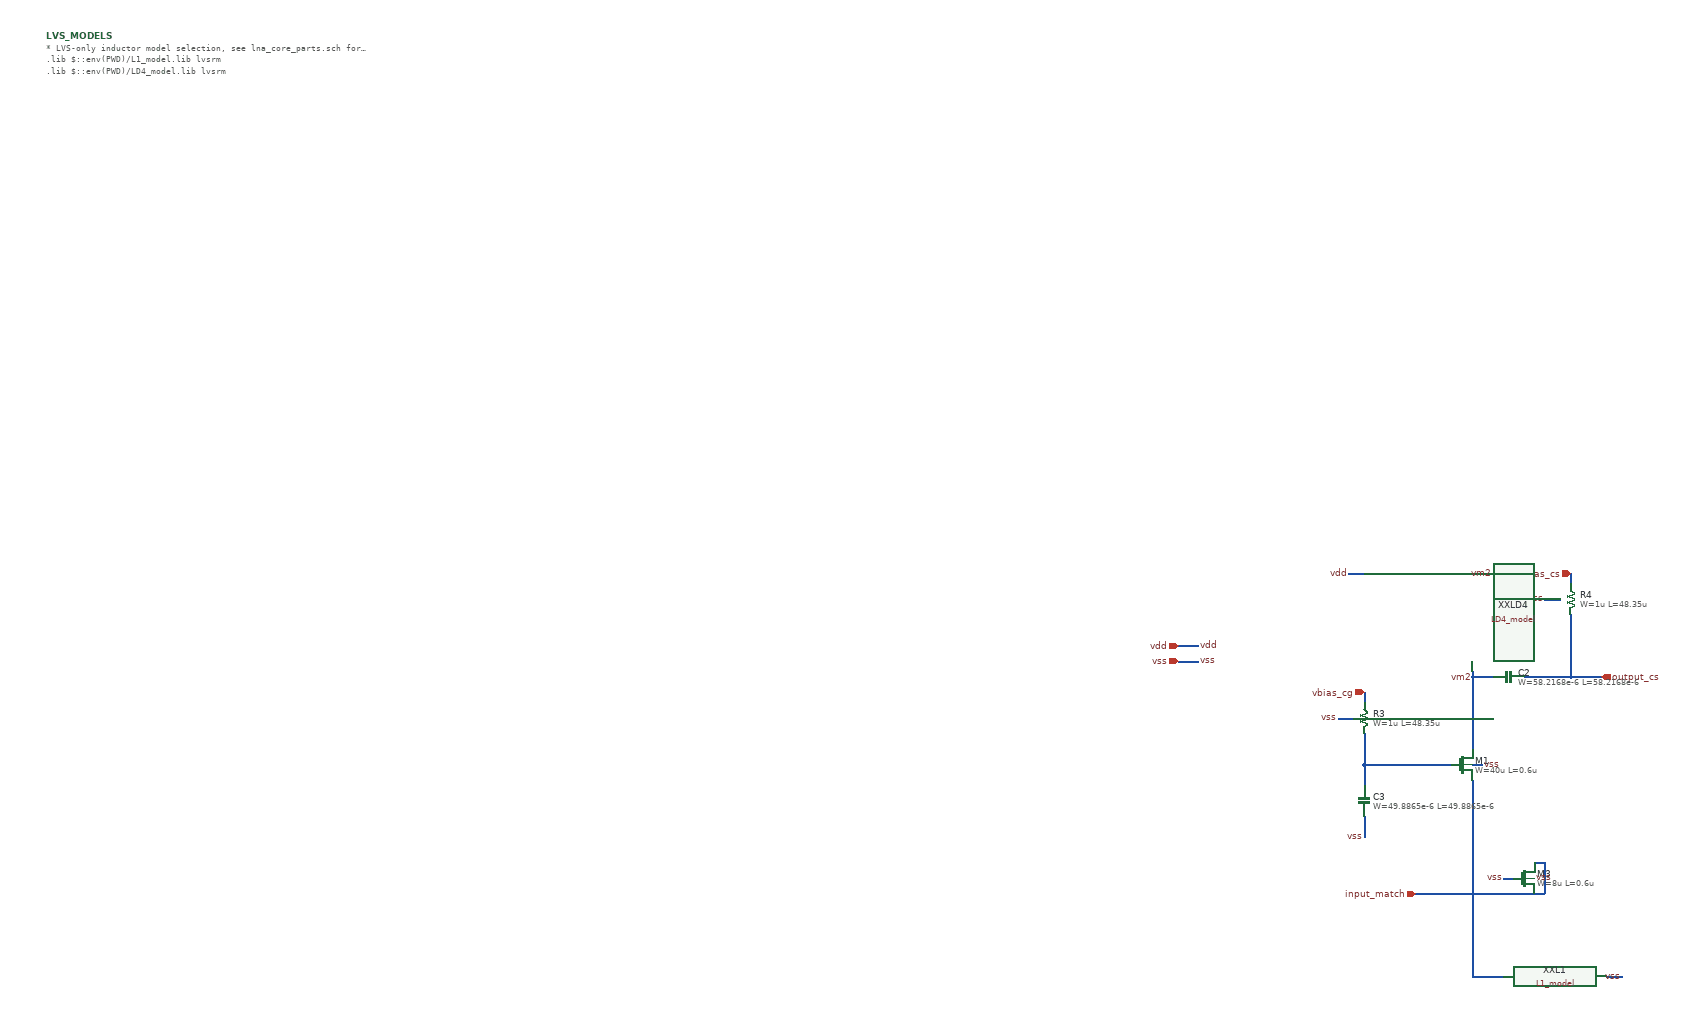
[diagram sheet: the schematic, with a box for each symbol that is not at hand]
v {xschem version=3.4.8RC file_version=1.3}
G {}
K {}
V {}
S {}
F {}
E {}
N 190 -790 230 -790 {lab=vss}
N 190 -820 230 -820 {lab=vdd}
N 760 -590 780 -590 {
lab=vss}
N 760 -760 800 -760 {
lab=vm2}
N 700 -590 720 -590 {
lab=#net1}
N 550 -730 550 -710 {
lab=vbias_cg}
N 550 -490 550 -450 {
lab=vss}
N 760 -660 760 -650 {
lab=vm2}
N 760 -650 760 -620 {lab=vm2}
N 760 -720 760 -660 {lab=vm2}
N 500 -680 530 -680 {lab=vss}
N 550 -590 550 -550 {lab=#net1}
N 550 -590 700 -590 {lab=#net1}
N 550 -650 550 -590 {lab=#net1}
N 760 -760 760 -720 {lab=vm2}
N 760 -380 760 -370 {
lab=input_match}
N 760 -370 760 -340 {
lab=input_match}
N 760 -560 760 -380 {lab=input_match}
N 760 -340 760 -320 {lab=input_match}
N 650 -340 760 -340 {lab=input_match}
N 760 -340 880 -340 {lab=input_match}
N 880 -400 900 -400 {lab=input_match}
N 900 -400 900 -340 {lab=input_match}
N 880 -340 900 -340 {lab=input_match}
N 820 -370 840 -370 {lab=vss}
N 760 -770 760 -760 {lab=vm2}
N 860 -760 900 -760 {
lab=output_cs}
N 950 -960 950 -940 {
lab=vbias_cs}
N 950 -880 950 -850 {
lab=output_cs}
N 900 -910 930 -910 {lab=vss}
N 900 -760 950 -760 {lab=output_cs}
N 950 -850 950 -760 {lab=output_cs}
N 950 -760 1010 -760 {lab=output_cs}
N 750 -960 780 -960 {lab=vm2}
N 780 -960 800 -960 {lab=vm2}
N 520 -960 550 -960 {lab=vdd}
N 760 -320 760 -180 {lab=input_match}
N 1020 -180 1050 -180 {lab=vss}
N 760 -180 820 -180 {lab=input_match}
C {ipin.sym} 650 -340 0 0 {name=p5 lab=input_match}
C {iopin.sym} 190 -820 2 0 {name=p4 lab=vdd}
C {iopin.sym} 190 -790 2 0 {name=p7 lab=vss}
C {lab_pin.sym} 230 -820 2 0 {name=p8 sig_type=std_logic lab=vdd
}
C {lab_pin.sym} 230 -790 2 0 {name=p9 sig_type=std_logic lab=vss
}
C {symbols/nfet_05v0.sym} 740 -590 0 0 {name=M1
L=0.6u
W=40u
nf=10
m=14
ad="'int((nf+1)/2) * W/nf * 0.18u'"
pd="'2*int((nf+1)/2) * (W/nf + 0.18u)'"
as="'int((nf+2)/2) * W/nf * 0.18u'"
ps="'2*int((nf+2)/2) * (W/nf + 0.18u)'"
nrd="'0.18u / W'" nrs="'0.18u / W'"
sa=0 sb=0 sd=0
model=nfet_05v0
spiceprefix=X
}
C {lab_pin.sym} 760 -758.75 0 0 {name=p15 sig_type=std_logic lab=vm2}
C {symbols/ppolyf_u_1k.sym} 550 -680 2 1 {name=R3
W=1u
L=48.35u
model=ppolyf_u_1k
spiceprefix=X
m=1}
C {iopin.sym} 550 -730 3 0 {name=p16 lab=vbias_cg}
C {lab_pin.sym} 550 -450 3 0 {name=p17 sig_type=std_logic lab=vss}
C {lab_pin.sym} 780 -590 2 0 {name=p18 sig_type=std_logic lab=vss}
C {lab_pin.sym} 500 -680 2 1 {name=p20 sig_type=std_logic lab=vss}
C {symbols/nfet_05v0.sym} 860 -370 0 0 {name=M3
L=0.6u
W=8u
nf=2
m=4
ad="'int((nf+1)/2) * W/nf * 0.18u'"
pd="'2*int((nf+1)/2) * (W/nf + 0.18u)'"
as="'int((nf+2)/2) * W/nf * 0.18u'"
ps="'2*int((nf+2)/2) * (W/nf + 0.18u)'"
nrd="'0.18u / W'" nrs="'0.18u / W'"
sa=0 sb=0 sd=0
model=nfet_05v0
spiceprefix=X
}
C {lab_pin.sym} 820 -370 0 0 {name=pM1 sig_type=std_logic lab=vss}
C {lab_pin.sym} 880 -370 2 0 {name=pM2 sig_type=std_logic lab=vss}
C {symbols/ppolyf_u_1k.sym} 950 -910 2 1 {name=R4
W=1u
L=48.35u
model=ppolyf_u_1k
spiceprefix=X
m=1}
C {iopin.sym} 950 -960 3 0 {name=p24 lab=vbias_cs
}
C {lab_pin.sym} 900 -910 2 1 {name=p25 sig_type=std_logic lab=vss}
C {opin.sym} 1010 -760 0 0 {name=p26 lab=output_cs}
C {LD4_model.sym} 650 -960 0 0 {name=XXLD4}
C {lab_pin.sym} 520 -960 1 0 {name=pRLD4_T1 sig_type=std_logic lab=vdd}
C {lab_pin.sym} 800 -960 1 0 {name=pRLD4_T2 sig_type=std_logic lab=vm2}
C {L1_model.sym} 920 -180 0 0 {name=XXL1}
C {lab_pin.sym} 1050 -180 1 0 {name=pRL1_T2 sig_type=std_logic lab=vss}
C {code_shown.sym} -2000 -2000 0 0 {name=LVS_MODELS only_toplevel=true
format="tcleval( @value )"
value="
* LVS-only inductor model selection, see lna_core_parts.sch for details.
.lib $::env(PWD)/L1_model.lib lvsrm
.lib $::env(PWD)/LD4_model.lib lvsrm
"}
C {symbols/cap_mim_2f0fF.sym} 550 -520 0 0 {name=C3
W=49.8865e-6
L=49.8865e-6
model=cap_mim_2f0fF
spiceprefix=X
m=4}
C {symbols/cap_mim_2f0fF.sym} 830 -760 3 0 {name=C2
W=58.2168e-6
L=58.2168e-6
model=cap_mim_2f0fF
spiceprefix=X
m=1}
